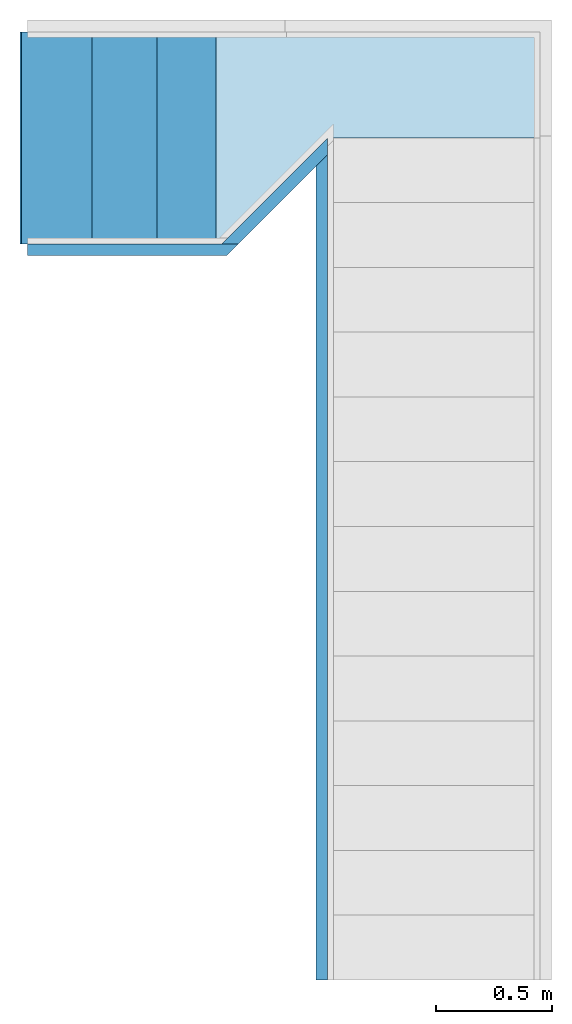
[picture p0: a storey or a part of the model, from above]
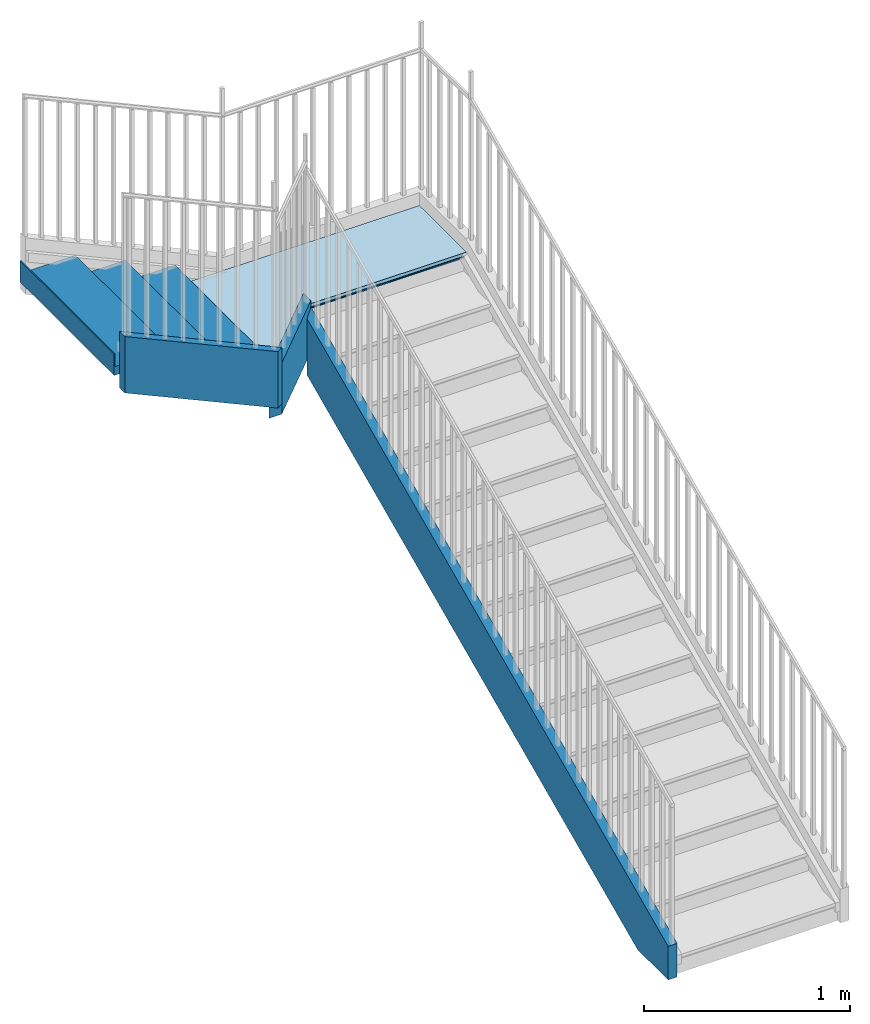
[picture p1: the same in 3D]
Properties of the parts of a building model (IFC2X3)

# File
Description: ViewDefinition [CoordinationView_V2.0]
File name: Project Number
Time: 2021-07-12T14:45:06
Written by: The EXPRESS Data Manager Version 5.02.0100.07 : 28 Aug 2013
Made in: 20180216_1515(x64) - Exporter 19.0.0.405 - 备用 UI 19.0.0.405
Comment: STEP Physical File produced by: The EXPRESS Data Manager Version 5.02.0100.07 : 28 Aug 2013 * Module: EDMstepFileFactory/EDMstandAlone * Creation date: Mon Jul 12 14:45:06 2021 * Host: DESKTOP-OMQ10H7 * Database: C:\Users\12580\AppData\Local\Temp\{0BB1D5D9-1BC5-407F-83F6-5A93C41D403B}\ifc * Database version: 5507 * Database creation date: Mon Jul 12 14:44:55 2021 * Schema: IFC2X3 * Model: DataRepository.ifc * Model creation date: Mon Jul 12 14:44:55 2021 * Header model: DataRepository.ifc_HeaderModel * Header model creation date: Mon Jul 12 14:44:55 2021 * EDMuser: sdai-user * EDMgroup: sdai-group * License ID and type: 5605 : Permanent license. Expiry date: * EDMstepFileFactory options: 020000

# IfcProject, Project Number
LongName: Project Name; Phase: Project Status

# IfcSite, 表面:237656
RefLatitude: 42, 21, 30, 344238; RefLongitude: -71, -3, -35, -194702; RefElevation: 0 ft

# IfcBuilding
Pset_BuildingCommon - NumberOfStoreys: 4

# IfcBuildingStorey (4)
Name | LongName | Elevation (ft)
HULL | HULL | -10
Level 1 | Level 1 | 0
Level 2 | Level 2 | 10
Sun Deck | Sun Deck | 20

# IfcBuildingElementProxy: 27" x 25" x 35", Dryer:27" x 25" x 35":377129
In: Level 2
Type - Classification: E1090400 Residential Equipment (Uniformat); Material: Metal - Paint Finish - Ivory, Glossy
Pset_BuildingElementProxyCommon - Reference: 27" x 25" x 35"

# IfcBuildingElementProxy: 27" x 25" x 35", Washer:27" x 25" x 35":376304
In: Level 2
Type - Classification: E1090400 Residential Equipment (Uniformat); Material: Metal - Paint Finish - Ivory, Matte
Pset_BuildingElementProxyCommon - Reference: 27" x 25" x 35"

# IfcBuildingElementProxy: 36" x 70", Refrigerator_built-in_SideBySide_stainlessrfa_5540:36" x 70":266599
In: Level 1
Type - Material: Metal - Stainless Steel, High Gloss Black
Pset_BuildingElementProxyCommon - Reference: 36" x 70"

# IfcBuildingElementProxy: 42_inch_plasma_tv_11107 (5)
Type - Material: glossy plastic, tv screen
Pset_BuildingElementProxyCommon - Reference: 42_inch_plasma_tv_11107
Name (42_inch_plasma_tv_11107:42_inch_plasma_tv_11107:...) | In
372576 | Sun Deck
372613 | Sun Deck
374357 | Level 2
375434 | Level 2
378181 | Level 2

# IfcBuildingElementProxy: 70039039_LED_TV_SONY_11909, 70039039_LED_TV_SONY_11909:70039039_LED_TV_SONY_11909:320596
In: Level 2
Material: Smooth - Black
Pset_BuildingElementProxyCommon - Reference: 70039039_LED_TV_SONY_11909

# IfcBuildingElementProxy: 72" (3)
In: Sun Deck
Material: Wood - Teak, Metal - Paint Finish - Dark Gray, Matte
Pset_BuildingElementProxyCommon - Reference: 72"
Name (Park Bench:72":...)
236447
236590
236649

# IfcBuildingElementProxy: Curvtec_Modular_Ceiling_with_lighting_11464, Curvtec_Modular_Ceiling_with_lighting_11464:Curvtec_Modular_Ceiling_with_lighting_11464:271074
In: Level 1
Type - Material: Glass - White, High Luminance, Wood Ceiling Black, Ceiling recess, Wood Ceiling
Pset_BuildingElementProxyCommon - Reference: Curvtec_Modular_Ceiling_with_lighting_11464

# IfcBuildingElementProxy: Mid_Size_Kitchen_-_Revit_2011_11227, Mid_Size_Kitchen_-_Revit_2011_11227:Mid_Size_Kitchen_-_Revit_2011_11227:266598
In: Level 1
Type - Material: Metal - Steel, Polished, range canopy, Stainless Steel Satin, Paint Black Glossy, Black Plastic (1), Brushed Aluminum Plastic, Cabinets - Handles, Wood - Cherry, Vidro Espelhado, Render Material 255-255-255, Stainless Steel, Cabinets, Dark Wood
Pset_BuildingElementProxyCommon - Reference: Mid_Size_Kitchen_-_Revit_2011_11227

# IfcBuildingElementProxy: Projection_Screen_4752, Projection_Screen_4752:Projection_Screen_4752:284235
In: Level 1
Type - Material: Screen, Case
Pset_BuildingElementProxyCommon - Reference: Projection_Screen_4752

# IfcBuildingElementProxy: RPC Notebook Computer (2)
In: Sun Deck
Pset_BuildingElementProxyCommon - Reference: RPC Notebook Computer
Name (RPC Notebook Computer:RPC Notebook Computer:...)
208535
208852

# IfcBuildingElementProxy: Scarlet Oak - 42' (13)
In: Level 1
Type - Classification: G2050500 Planting (Uniformat)
Pset_BuildingElementProxyCommon - Reference: Scarlet Oak - 42'
Name (RPC Tree - Deciduous:Scarlet Oak - 42':...)
322992
323077
323106
323141
323178
323237
323296
323366
323413
323432
323502
323537
323560

# IfcBuildingElementProxy: Standard, Cage Ladder:Standard:312129
In: Sun Deck
Pset_BuildingElementProxyCommon - Reference: Standard

# IfcBuildingElementProxy: Tall_Speaker_2545 (8)
In: Level 1
Type - Material: Speaker, Gloss White
Pset_BuildingElementProxyCommon - Reference: Tall_Speaker_2545
Name (Tall_Speaker_2545:Tall_Speaker_2545:...)
287609
287684
287761
287830
288329
288446
288509
288600

# IfcCovering: 复合天花板:GWB on Mtl. Stud (7)
PredefinedType: CEILING; Classification: C3030220 Suspended Ceilings - Gypsum Board (Uniformat); Material: Metal - Stud Layer 0.302083 ft, Gypsum Wall Board 0.0520833 ft
Pset_CoveringCommon - Reference: GWB on Mtl. Stud; Finish: Gypsum Wall Board;; TotalThickness: 0.354167 ft
Name (复合天花板:GWB on Mtl. Stud:...) | In
188560 | Level 2
189789 | Sun Deck
192301 | Sun Deck
267230 | Level 1
267281 | Level 1
301652 | Level 1
349367 | Level 2

# IfcDoor: 30" x 80", Single-Flush:30" x 80":341240
In: Level 2
Type - OperationType: SINGLE_SWING_LEFT; ParameterTakesPrecedence: no; Sizeable: no; Classification: C1020 Interior Doors (Uniformat); Material: Door - Frame, Door - Panel
Type - Single-Flush:30" x 80":341240 - PanelOperation: SWINGING
OverallHeight: 6.66667 ft; OverallWidth: 2.5 ft
Pset_DoorCommon - IsExternal: no; Reference: 30" x 80"

# IfcDoor: 30" x 80", Single-Glass 2:30" x 80":267189
In: Level 1
Type - OperationType: SINGLE_SWING_LEFT; ParameterTakesPrecedence: no; Sizeable: no; Classification: C1020 Interior Doors (Uniformat); Material: Door - Frame, Door - Panel, Glass
Type - Single-Glass 2:30" x 80":267189 - PanelOperation: SWINGING
OverallHeight: 6.66667 ft; OverallWidth: 2.5 ft
Pset_DoorCommon - IsExternal: no; Reference: 30" x 80"

# IfcDoor: 30" x 80" (2)
In: Level 2
Type - OperationType: SINGLE_SWING_RIGHT; ParameterTakesPrecedence: no; Sizeable: no; Classification: C1020 Interior Doors (Uniformat); Material: Door - Frame, Door - Panel
Type - Single-Flush:30" x 80":331799 - PanelOperation: SWINGING
OverallHeight: 6.66667 ft; OverallWidth: 2.5 ft
Pset_DoorCommon - IsExternal: no; Reference: 30" x 80"
Name (Single-Flush:30" x 80":...)
331799
341395

# IfcDoor: 30" x 80", Single-Flush:30" x 80":344412
In: Level 2
Type - OperationType: SINGLE_SWING_RIGHT; ParameterTakesPrecedence: no; Sizeable: no; Classification: C1020 Interior Doors (Uniformat); Material: Door - Frame, Door - Panel
Type - Single-Flush:30" x 80":344412 - PanelOperation: SWINGING
OverallHeight: 6.66667 ft; OverallWidth: 2.5 ft
Pset_DoorCommon - IsExternal: no; Reference: 30" x 80"

# IfcDoor: 30" x 84", Single-Glass 2:30" x 84":328122
In: Level 2
Type - OperationType: SINGLE_SWING_LEFT; ParameterTakesPrecedence: no; Sizeable: no; Classification: C1020 Interior Doors (Uniformat); Material: Door - Frame, Door - Panel, Glass
Type - Single-Glass 2:30" x 84":328122 - PanelOperation: SWINGING
OverallHeight: 7 ft; OverallWidth: 3 ft
Pset_DoorCommon - IsExternal: no; Reference: 30" x 84"

# IfcDoor: 30" x 84", Single-Glass 2:30" x 84":336054
In: Level 2
Type - OperationType: SINGLE_SWING_RIGHT; ParameterTakesPrecedence: no; Sizeable: no; Classification: C1020 Interior Doors (Uniformat); Material: Door - Frame, Door - Panel, Glass
Type - Single-Glass 2:30" x 84":336054 - PanelOperation: SWINGING
OverallHeight: 7 ft; OverallWidth: 3 ft
Pset_DoorCommon - IsExternal: no; Reference: 30" x 84"

# IfcDoor: 32" x 84" (2)
In: Level 1
Type - OperationType: SINGLE_SWING_RIGHT; ParameterTakesPrecedence: no; Sizeable: no; Classification: C1020 Interior Doors (Uniformat); Material: Door - Frame, Door - Panel
Type - Single-Flush:32" x 84":314709 - PanelOperation: SWINGING
OverallHeight: 7 ft; OverallWidth: 2.66667 ft
Pset_DoorCommon - IsExternal: no; Reference: 32" x 84"
Name (Single-Flush:32" x 84":...)
314709
314761

# IfcDoor: 48" x 84" (2)
In: Level 2
Type - ParameterTakesPrecedence: no; Sizeable: no; Classification: C1020 Interior Doors (Uniformat); Material: Door - Panel, Door - Frame
OverallHeight: 5 ft; OverallWidth: 4 ft
Pset_DoorCommon - IsExternal: no; Reference: 48" x 84"
Name (Bifold-4 Panel:48" x 84":...)
337613
339624

# IfcDoor: 60" x 84" (3)
In: Level 2
Type - ParameterTakesPrecedence: no; Sizeable: no; Classification: C1020 Interior Doors (Uniformat); Material: Door - Panel, Door - Frame
OverallHeight: 7 ft; OverallWidth: 5 ft
Pset_DoorCommon - IsExternal: no; Reference: 60" x 84"
Name (Bifold-4 Panel:60" x 84":...)
336918
371404
371428

# IfcDoor: 68" x 84" (4)
Type - ParameterTakesPrecedence: no; Sizeable: no; Classification: C1020 Interior Doors (Uniformat); Material: Glass, Door - Panel, Door - Frame
OverallHeight: 7 ft; OverallWidth: 5.66667 ft
Pset_DoorCommon - IsExternal: no; Reference: 68" x 84"
Name (Sliding-2 panel:68" x 84":...) | In
323940 | Level 2
323982 | Level 2
325066 | Level 1
325091 | Level 1

# IfcDoor: 72" x 84" (10)
Type - ParameterTakesPrecedence: no; Sizeable: no; Classification: C1020 Interior Doors (Uniformat); Material: Glass, Door - Panel, Door - Frame
OverallHeight: 7 ft; OverallWidth: 10 ft
Pset_DoorCommon - IsExternal: yes; Reference: 72" x 84"
Name (Sliding-2 panel:72" x 84":...) | In
312039 | Level 1
312078 | Level 1
312933 | Level 1
313002 | Level 1
322042 | Level 2
322064 | Level 2
322137 | Level 2
322168 | Level 2
322806 | Sun Deck
322843 | Sun Deck

# IfcFlowTerminal: 100W - 120V (24)
In: Level 1
Type - Classification: D5020220 Lighting - Incandescent (Uniformat); Material: Metal - Paint Finish - Dark Gray, Matte, Glass - White, High Luminance
Pset_DistributionFlowElementCommon - Reference: 100W - 120V
Name (Ceiling Light - Flat Round:100W - 120V:...)
272236
272435
272723
272951
273287
273575
274187
275483
275795
276107
276755
276983
277403
277763
278135
278411
302545
302617
302785
303025
303313
303577
303865
304669

# IfcFlowTerminal: 100W - 277V (41)
In: Level 2
Type - Classification: D5020220 Lighting - Incandescent (Uniformat); Material: Metal - Paint Finish - Dark Gray, Matte, Glass - White, High Luminance
Pset_DistributionFlowElementCommon - Reference: 100W - 277V
Name (Ceiling Light - Flat Round:100W - 277V:...)
350810
350911
351163
351763
351955
352207
352423
352699
352927
353167
353551
353815
353959
354559
355183
355351
356023
356671
356839
356995
358003
358255
358591
358831
359455
359683
359911
360151
360655
360955
361351
361843
362431
362827
363091
363391
363547
363703
364075
364987
365203

# IfcFlowTerminal: 15" Seat Height (4)
Classification: D2010110 Water Closets - Single (Uniformat); Material: Porcelain - Ivory, Laminate - Ivory, Matte, Metal - Steel, Polished
Pset_DistributionFlowElementCommon - Reference: 15" Seat Height
Name (Toilet-Commercial-Wall-3D:15" Seat Height:...) | In
315608 | Level 1
331035 | Level 2
331502 | Level 2
341191 | Level 2

# IfcFlowTerminal: 30" x 60" (2)
In: Level 2
Classification: D2010110 Water Closets - Single (Uniformat); Material: Porcelain - Ivory
Pset_DistributionFlowElementCommon - Reference: 30" x 60"
Name (Tub-Free Standing-3D:30" x 60":...)
329077
332994

# IfcFlowTerminal: 52quot_Surface_Ceiling_Fan_Retro_look_11276 (13)
Type - Material: Light Bulb, Glass - Frosted, Black Out, Plastic - White
Pset_DistributionFlowElementCommon - Reference: 52quot_Surface_Ceiling_Fan_Retro_look_11276
Name (52quot_Surface_Ceiling_Fan_Retro_look_11276:52quot_Surface_Ceiling_Fan_Retro_look_11276:...) | In
299501 | Level 1
299546 | Level 1
300126 | Level 1
300866 | Level 1
302015 | Level 1
302113 | Level 1
366261 | Level 2
366329 | Level 2
366649 | Level 2
367009 | Level 2
367279 | Level 2
367749 | Level 2
368369 | Level 2

# IfcFlowTerminal: 60W - 120V (12)
In: Sun Deck
Type - Classification: D5020220 Lighting - Incandescent (Uniformat); Material: Metal - Paint Finish - Dark Gray, Matte, Glass - White, High Luminance
Pset_DistributionFlowElementCommon - Reference: 60W - 120V
Name (Ceiling Light - Flat Round:60W - 120V:...)
211935
212036
212252
212480
212948
213164
213344
213536
214304
214616
215036
215408

# IfcFurnishingElement: 24" Depth (5)
Type - ElementType: 24" Depth; Classification: C1030400 Fabricated Cabinets & Counters (Uniformat); Material: Counter Top
Name (Vanity Counter Top w Round Sink Hole:24" Depth:...) | In
317033 | Level 1
329369 | Level 2
332200 | Level 2
332346 | Level 2
377366 | Level 2

# IfcFurnishingElement: 24" x 24", Table-End:24" x 24":348298
In: Level 2
Type - ElementType: 24" x 24"; Classification: E2020200 Furniture & Accessories (Uniformat); Material: Laminate - Ivory, Matte, Wood - Birch

# IfcFurnishingElement: 27", Television:27":369105
In: Level 2
Type - ElementType: 27"; Classification: E2020200 Furniture & Accessories (Uniformat); Material: Plastic - Gray, Glass

# IfcFurnishingElement: 30" x 84" x 22", Table-Dining:30" x 84" x 22":279648
In: Level 1
Type - ElementType: 30" x 84" x 22"; Classification: E2020200 Furniture & Accessories (Uniformat); Material: Metal - Chrome, Glass - Clear, Grey

# IfcFurnishingElement: 36" Diameter (2)
In: Level 2
Type - ElementType: 36" Diameter; Classification: E2020200 Furniture & Accessories (Uniformat); Material: Metal - Chrome, Wood - Birch
Name (Table-Round:36" Diameter:...)
375108
375185

# IfcFurnishingElement: 36" Diameter (3)
Type - ElementType: 36" Diameter; Classification: E2020200 Furniture & Accessories (Uniformat); Material: Wood - Pine, Laminate - Linen, Matte
Name (Table-Dining Round w Chairs:36" Diameter:...) | In
233616 | Level 1
233758 | Sun Deck
233853 | Sun Deck

# IfcFurnishingElement: 48" (2)
Type - ElementType: 48"; Classification: C1030410 Cabinets (Uniformat); Material: Cabinets - Handles, Cabinets
Name (Vanity Cabinet-Double Door & 4 Drawer:48":...) | In
316380 | Level 1
341020 | Level 2

# IfcFurnishingElement: 48" (3)
In: Level 2
Type - ElementType: 48"; Classification: C1030410 Cabinets (Uniformat); Material: Cabinets, Cabinets - Handles
Name (Base Cabinet-Double Door Sink Unit:48":...)
329719
332070
377529

# IfcFurnishingElement: 72", Sofa:72":378009
In: Level 2
Type - ElementType: 72"; Classification: E2020200 Furniture & Accessories (Uniformat); Material: Wood - Cherry, Textile - Linen, Smooth

# IfcFurnishingElement: 72" x 72" x 24" (2)
In: Level 2
Type - ElementType: 72" x 72" x 24"; Classification: E2020200 Furniture & Accessories (Uniformat); Material: Metal - Chrome, Glass - Clear, Grey
Name (Entertainment Center:72" x 72" x 24":...)
334129
345260

# IfcFurnishingElement: 82" x 36" (2)
In: Level 2
Type - ElementType: 82" x 36"; Classification: E2020200 Furniture & Accessories (Uniformat); Material: Wood - Birch, Textile - White
Name (Bed-Bunk:82" x 36":...)
343888
344183

# IfcFurnishingElement: BED_9020 (2)
In: Level 2
Type - ElementType: BED_9020; Material: Metal - Paint Finish - Ivory, Glossy, Glass - White, High Luminance, ss, black, shine, garment, wood brown
Name (BED_9020:BED_9020:...)
319784
326286

# IfcFurnishingElement: Chair-Breuer (26)
Type - ElementType: Chair-Breuer; Classification: E2020200 Furniture & Accessories (Uniformat); Material: Textile - Bamboo Weave, Metal - Chrome
Name (Chair-Breuer:Chair-Breuer:...) | In
233618 | Level 1
233619 | Level 1
233620 | Level 1
233621 | Level 1
233622 | Level 1
233623 | Level 1
233760 | Sun Deck
233761 | Sun Deck
233762 | Sun Deck
233763 | Sun Deck
233764 | Sun Deck
233765 | Sun Deck
233855 | Sun Deck
233856 | Sun Deck
233857 | Sun Deck
233858 | Sun Deck
233859 | Sun Deck
233860 | Sun Deck
280343 | Level 1
280508 | Level 1
280549 | Level 1
280588 | Level 1
280641 | Level 1
280700 | Level 1
280793 | Level 1
280983 | Level 1

# IfcFurnishingElement: Chair-Corbu (6)
In: Level 2
Type - ElementType: Chair-Corbu; Classification: E2020200 Furniture & Accessories (Uniformat); Material: Textile - Black, Metal - Chrome
Name (Chair-Corbu:Chair-Corbu:...)
334675
339712
341920
342243
374127
374248

# IfcFurnishingElement: Chair-Executive, Chair-Executive:Chair-Executive:346257
In: Level 2
Type - ElementType: Chair-Executive; Classification: E2020200 Furniture & Accessories (Uniformat); Material: Plastic - Black, Textile - Slate Blue

# IfcFurnishingElement: Coffee_table_10605, Coffee_table_10605:Coffee_table_10605:305432
In: Level 1
Type - ElementType: Coffee_table_10605; Material: Speaker Body

# IfcFurnishingElement: Histoire_Round_Bed_10479, Histoire_Round_Bed_10479:Histoire_Round_Bed_10479:325919
In: Level 2
Type - ElementType: Histoire_Round_Bed_10479; Material: Blue Leather, Dark Wood

# IfcFurnishingElement: Hot_Tub_4137, Hot_Tub_4137:Hot_Tub_4137:264282
In: Level 1
Type - ElementType: Hot_Tub_4137; Material: Site - Water, Wood - Pine

# IfcFurnishingElement: Modern_Office_Desk_8428, Modern_Office_Desk_8428:Modern_Office_Desk_8428:370810
In: Level 2
Type - ElementType: Modern_Office_Desk_8428; Material: Glass, Metal, Cherry

# IfcFurnishingElement: Sofa_6855, Sofa_6855:Sofa_6855:264052
In: Level 1
Type - ElementType: Sofa_6855; Material: Blue Leather

# IfcFurnishingElement: Theater_Seating_2459, Theater_Seating_2459:Theater_Seating_2459:286273
In: Level 1
Type - ElementType: Theater_Seating_2459; Material: Default

# IfcFurnishingElement: armchair_12444 (3)
In: Sun Deck
Type - ElementType: armchair_12444; Material: legs, cushion 9, cushion 6
Name (armchair_12444:armchair_12444:...)
373716
373787
373836

# IfcFurnishingElement: pool_table_11855, pool_table_11855:pool_table_11855:278966
In: Level 1
Type - ElementType: pool_table_11855; Material: wood 26t, felt, pocket

# IfcMember: 楼梯:7" max riser 11" tread:54873 (28)
Classification: C Interiors (Uniformat); Material: Metal - Aluminum
Pset_MemberCommon - Reference: 7" max riser 11" tread; LoadBearing: yes; IsExternal: yes
Name (楼梯:7" max riser 11" tread:...) | In
162685:1 | Level 1 | Pset_MemberCommon - Span: 0.166667 ft; Slope: 0 deg
162685:2 | Level 1 | Pset_MemberCommon - Span: 0.166667 ft; Slope: 0 deg
163019:1 | Level 1 | Pset_MemberCommon - Span: 0.166667 ft; Slope: 0 deg
163019:2 | Level 1 | Pset_MemberCommon - Span: 0.166667 ft; Slope: 0 deg
163560:1 | Level 1 | Pset_MemberCommon - Span: 0.166667 ft; Slope: 0 deg
163560:2 | Level 1 | Pset_MemberCommon - Span: 0.166667 ft; Slope: 0 deg
168170:1 | HULL
168170:2 | HULL
168170:3 | HULL
168170:4 | HULL | Pset_MemberCommon - Span: 1 ft; Slope: 0 deg
168392:1 | Level 1
168392:2 | Level 1
168392:3 | Level 1 | Pset_MemberCommon - Span: 1 ft; Slope: 0 deg
168392:4 | Level 1
182033:1 | Level 2
182033:2 | Level 2
182033:3 | Level 2 | Pset_MemberCommon - Span: 1 ft; Slope: 0 deg
182033:4 | Level 2
199630:1 | Level 1
199630:2 | Level 1
199630:3 | Level 1
199630:4 | Level 1 | Pset_MemberCommon - Span: 1 ft; Slope: 0 deg
202250:1 | Level 2
202250:2 | Level 2
202250:3 | Level 2 | Pset_MemberCommon - Span: 1 ft; Slope: 0 deg
202250:4 | Level 2 | Pset_MemberCommon - Span: 0.166667 ft; Slope: 0 deg
314511:1 | Level 1 | Pset_MemberCommon - Span: 0.166667 ft; Slope: 0 deg
314511:2 | Level 1 | Pset_MemberCommon - Span: 0.166667 ft; Slope: 0 deg

# IfcOpeningElement: Opening (79)
Name | In
2 x  | Level 1 | Classification: B1010 Floor Construction (Uniformat)
5 x  | Level 2 | Classification: B1010 Floor Construction (Uniformat)
楼板:LW Concrete on Metal Deck:175324:2 | Level 2 | Classification: B1010 Floor Construction (Uniformat)
Bifold-4 Panel:60" x 84":371404:1 | Level 2
Bifold-4 Panel:60" x 84":371428:1 | Level 2
基本墙:Generic - 4" Brick:307458 | Level 2 | Classification: B2010 Exterior Walls (Uniformat)
基本墙:Generic - 4" Brick:309413 | Level 1 | Classification: B2010 Exterior Walls (Uniformat)
Vanity Counter Top w Round Sink Hole:24" Depth:317033:1 | Level 1 | Classification: C1030400 Fabricated Cabinets & Counters (Uniformat)
楼板:LW Concrete on Metal Deck:317237:2 | Level 2 | Classification: B1010 Floor Construction (Uniformat)
 | Sun Deck | Classification: B1010 Floor Construction (Uniformat)
Single-Flush:30" x 80":344412:1 | Level 2
Vanity Counter Top w Round Sink Hole:24" Depth:329369:1 | Level 2 | Classification: C1030400 Fabricated Cabinets & Counters (Uniformat)
Vanity Counter Top w Round Sink Hole:24" Depth:332200:1 | Level 2 | Classification: C1030400 Fabricated Cabinets & Counters (Uniformat)
Vanity Counter Top w Round Sink Hole:24" Depth:332346:1 | Level 2 | Classification: C1030400 Fabricated Cabinets & Counters (Uniformat)
Single-Flush:30" x 80":341240:1 | Level 2
Vanity Counter Top w Round Sink Hole:24" Depth:377366:1 | Level 2 | Classification: C1030400 Fabricated Cabinets & Counters (Uniformat)
Bifold-4 Panel:48" x 84":339624:1 | Level 2
Single-Glass 2:30" x 80":267189:1 | Level 1
Slider with Trim:48" x 48":331066:1 | Level 2
Sliding-2 panel:72" x 84":322042:1 | Level 2
Slider with Trim:48" x 48":322226:1 | Level 2
Slider with Trim:48" x 48":322263:1 | Level 2
Slider with Trim:48" x 48":322329:1 | Level 2
Slider with Trim:48" x 48":322571:1 | Level 2
Slider with Trim:48" x 48":337709:1 | Level 2
Slider with Trim:48" x 48":342144:1 | Level 2
Sliding-2 panel:72" x 84":322137:1 | Level 2
Sliding-2 panel:72" x 84":322168:1 | Level 2
Sliding-2 panel:72" x 84":322064:1 | Level 2
Slider with Trim:48" x 48":322369:1 | Level 2
Slider with Trim:48" x 48":322411:1 | Level 2
Slider with Trim:48" x 48":322455:1 | Level 2
Slider with Trim:48" x 48":331716:1 | Level 2
Slider with Trim:48" x 48":342172:1 | Level 2
Sliding-2 panel:68" x 84":323982:1 | Level 2
Sliding-2 panel:68" x 84":323940:1 | Level 2
Slider with Trim:48" x 48":323922:1 | Level 2
Slider with Trim:48" x 48":322567:1 | Level 2
Slider with Trim:48" x 48":342203:1 | Level 2
Slider with Trim:48" x 48":342191:1 | Level 2
Sliding-2 panel:72" x 84":313002:1 | Level 1
Slider with Trim:48" x 48":314223:1 | Level 1
Slider with Trim:48" x 48":314252:1 | Level 1
Sliding-2 panel:72" x 84":312039:1 | Level 1
Sliding-2 panel:72" x 84":312078:1 | Level 1
Sliding-2 panel:72" x 84":312933:1 | Level 1
Slider with Trim:48" x 48":314029:1 | Level 1
Slider with Trim:48" x 48":314059:1 | Level 1
Slider with Trim:48" x 48":314088:1 | Level 1
Slider with Trim:48" x 48":314110:1 | Level 1
Slider with Trim:36" x 48":312009:1 | Level 1
Slider with Trim:36" x 48":312024:1 | Level 1
Sliding-2 panel:68" x 84":325066:1 | Level 1
Sliding-2 panel:68" x 84":325091:1 | Level 1
Slider with Trim:48" x 48":314162:1 | Level 1
Slider with Trim:48" x 48":325255:1 | Level 1
Slider with Trim:48" x 48":325135:1 | Level 1
Slider with Trim:48" x 48":325177:1 | Level 1
Slider with Trim:60" x 48":322711:1 | Sun Deck
Slider with Trim:60" x 48":322750:1 | Sun Deck
Sliding-2 panel:72" x 84":322806:1 | Sun Deck
Sliding-2 panel:72" x 84":322843:1 | Sun Deck
Slider with Trim:48" x 48":322792:1 | Sun Deck
Slider with Trim:48" x 48":322796:1 | Sun Deck
Slider with Trim:48" x 48":314132:1 | Level 1
Slider with Trim:48" x 48":325219:1 | Level 1
Single-Flush:32" x 84":314761:1 | Level 1
Single-Flush:32" x 84":314709:1 | Level 1
Single-Glass 2:30" x 84":328122:1 | Level 2
Single-Glass 2:30" x 84":336054:1 | Level 2
Single-Flush:30" x 80":341395:1 | Level 2
Single-Flush:30" x 80":331799:1 | Level 2
Bifold-4 Panel:60" x 84":336918:1 | Level 2
Bifold-4 Panel:48" x 84":337613:1 | Level 2

# IfcRailing: 栏杆扶手:Handrail - Rectangular (23)
Classification: C2010400 Stair Handrails/Balustrades (Uniformat)
Pset_RailingCommon - IsExternal: no; Reference: Handrail - Rectangular; Height: 4 ft
Name (栏杆扶手:Handrail - Rectangular:...) | In
162701 | Level 1
162705 | Level 1
163027 | Level 1
163031 | Level 1
168229 | HULL
168233 | HULL
168422 | Level 1
168426 | Level 1
170974 | Level 1
171574 | Level 1
172054 | Level 1
179988 | Level 2
182085 | Level 2
182089 | Level 2
200027 | Level 1
200031 | Level 1
201111 | Level 2
202295 | Level 2
202299 | Level 2
202742 | Sun Deck
203479 | Sun Deck
314527 | Level 1
314531 | Level 1

# IfcSlab: 楼板:3" LW Concrete on 2" Metal Deck, 楼板:3" LW Concrete on 2" Metal Deck:324292
In: Sun Deck
PredefinedType: FLOOR; Classification: B1010 Floor Construction (Uniformat); Material: Carpet (2) 0.25 ft
Pset_SlabCommon - LoadBearing: no; IsExternal: no; Reference: 3" LW Concrete on 2" Metal Deck

# IfcSlab: 楼板:LW Concrete on Metal Deck (10)
PredefinedType: FLOOR; Classification: B1010 Floor Construction (Uniformat); Material: Metal - Deck 0.333333 ft, Carpet (2) 0.0104167 ft
Pset_SlabCommon - LoadBearing: no; IsExternal: no; Reference: LW Concrete on Metal Deck
Name (楼板:LW Concrete on Metal Deck:...) | In | PitchAngle (deg)
161527 | Level 1 | 0
162236 | Level 1
169581 | Level 1 | 0
175324 | Level 2
176802 | Level 2 | 0
178148 | Level 1 | 0
179185 | Level 2
202447 | Sun Deck | 0
317237 | Level 2
318822 | Level 2 | 0

# IfcSlab: 楼梯:7" max riser 11" tread:54873 (5)
PredefinedType: LANDING; Classification: C Interiors (Uniformat); Material: Metal - Aluminum
Pset_SlabCommon - Reference: 7" max riser 11" tread; IsExternal: yes
Name (楼梯:7" max riser 11" tread:...) | In
168170:1 | HULL
168392:1 | Level 1
182033:1 | Level 2
199630:1 | Level 1
202250:1 | Level 2

# IfcStair: 楼梯:7" max riser 11" tread:54873 (9)
Classification: C Interiors (Uniformat)
Pset_StairCommon - Reference: 7" max riser 11" tread; IsExternal: yes; TreadLength: 0.916667 ft
Name (楼梯:7" max riser 11" tread:...) | In | NumberOfRiser | NumberOfTreads | RiserHeight (ft)
162685 | Level 1 | 3 | 2 | 0.558824
163019 | Level 1 | 3 | 2 | 0.558824
163560 | Level 1 | 3 | 2 | 0.558824
168170 | HULL | 18 | 17 | 0.416667
168392 | Level 1 | 18 | 17 | 0.555556
182033 | Level 2 | 18 | 17 | 0.555556
199630 | Level 1 | 18 | 17 | 0.569444
202250 | Level 2 | 18 | 17 | 0.555556
314511 | Level 1 | 3 | 2 | 0.555556

# IfcStairFlight: 楼梯:7" max riser 11" tread:54873 (14)
Classification: C Interiors (Uniformat); Material: Metal - Aluminum
Pset_StairFlightCommon - Reference: 7" max riser 11" tread; TreadLength: 0.916667 ft; TreadLengthAtOffset: 0.916667 ft; TreadLengthAtInnerSide: 0.0833333 ft; NosingLength: 0.916667 ft
Name (楼梯:7" max riser 11" tread:...) | In | NumberOfRiser | NumberOfTreads | RiserHeight (ft) = Pset_StairFlightCommon, RiserHeight (ft) | TreadLength (ft) | Pset_StairFlightCommon, NumberOfRiser | Pset_StairFlightCommon, NumberOfTreads | WalkingLineOffset (ft) | WaistThickness (ft)
162685:1 | Level 1 | 3 | 2 | 0.558824 | 0.916667 | 3 | 2 | 1.79167 | 3.58333
163019:1 | Level 1 | 3 | 2 | 0.558824 | 0.916667 | 3 | 2 | 1.75 | 3.5
163560:1 | Level 1 | 3 | 2 | 0.558824 | 0.916667 | 3 | 2 | 2 | 4
168170:1 | HULL | 14 | 13 | 0.416667 | 0.916667 | 18 | 17 | 1.5 | 3
168170:2 | HULL | 4 | 3 | 0.416667 | 0.916667 | 18 | 17 | 1.5 | 3
168392:1 | Level 1 | 4 | 3 | 0.555556 | 0.916667 | 18 | 17 | 1.5 | 3
168392:2 | Level 1 | 14 | 13 | 0.555556 | 0.916667 | 18 | 17 | 1.5 | 3
182033:1 | Level 2 | 4 | 3 | 0.555556 | 0.951389 | 18 | 17 | 1.5 | 3
182033:2 | Level 2 | 14 | 13 | 0.555556 | 0.916667 | 18 | 17 | 1.5 | 3
199630:1 | Level 1 | 16 | 15 | 0.569444 | 0.916667 | 18 | 17 | 1.5 | 3
199630:2 | Level 1 | 2 | 1 | 0.569444 | 0.916667 | 18 | 17 | 1.5 | 3
202250:1 | Level 2 | 2 | 1 | 0.555556 | 0.916667 | 18 | 17 | 1.5 | 3
202250:2 | Level 2 | 16 | 15 | 0.555556 | 0.916667 | 18 | 17 | 1.5 | 3
314511:1 | Level 1 | 3 | 2 | 0.555556 | 0.977867 | 3 | 2 | 1.75 | 3.5

# IfcWallStandardCase: 基本墙:Generic - 4" Brick (44)
Type - PredefinedType: STANDARD; Material: Paint 0.333333 ft, Paints and Coatings 0.166667 ft
Classification: B2010 Exterior Walls (Uniformat)
Pset_WallCommon - Reference: Generic - 4" Brick; LoadBearing: no; IsExternal: no
Name (基本墙:Generic - 4" Brick:...) | In | ExtendToStructure
161342 | Level 1 | no
161385 | Level 1 | no
161434 | Level 1 | no
161481 | Level 1 | no
163274 | Level 1 | yes
169023 | Level 1 | yes
169086 | Level 1 | yes
169295 | Level 1 | yes
169467 | Level 1 | yes
169516 | Level 1 | yes
169564 | Level 1 | yes
201977 | Level 2 | no
202191 | Level 2 | no
267019 | Level 1 | yes
307288 | Level 2 | no
307338 | Level 2 | no
307390 | Level 2 | no
307434 | Level 2 | no
307448 | Level 2 | no
307453 | Level 2 | no
307458 | Level 2 | no
307463 | Level 2 | no
307783 | Level 1 | yes
307841 | Level 1 | no
307897 | Level 1 | yes
307906 | Level 1 | no
307911 | Level 1 | no
309315 | Level 1 | yes
309359 | Level 1 | yes
309413 | Level 1 | no
309418 | Level 1 | yes
310853 | Sun Deck | no
310926 | Sun Deck | no
310995 | Sun Deck | no
311076 | Sun Deck | no
311140 | Sun Deck | no
311145 | Sun Deck | no
311150 | Sun Deck | no
311155 | Sun Deck | no
311675 | Level 1 | yes
314343 | Level 1 | yes
314392 | Level 1 | yes
314691 | Level 1 | yes
344382 | Level 2 | no

# IfcWallStandardCase: 基本墙:Interior - 3 1/8" Partition (1-hr) (23)
In: Level 2
Type - PredefinedType: STANDARD; Material: Gypsum Wall Board 0.0416667 ft, Gypsum Wall Board 0.0208333 ft, Metal - Stud Layer 0.135417 ft, Gypsum Wall Board 0.0208333 ft, Gypsum Wall Board 0.0416667 ft
Classification: C1010145 Partitions - Drywall w/ Metal Stud (Uniformat)
Pset_WallCommon - LoadBearing: no; ExtendToStructure: no; IsExternal: no; Reference: Interior - 3 1/8" Partition (1-hr)
Name (基本墙:Interior - 3 1/8" Partition (1-hr):...)
320325
327329
327517
327601
330925
331646
336532
336579
337480
337533
339567
339606
340040
341836
342554
342596
342631
342696
342759
342805
342927
371281
371325

# IfcWindow: 36" x 48" (2)
In: Level 1
Type - ParameterTakesPrecedence: no; Sizeable: no; Classification: B2020100 Windows (Uniformat); Material: Glass, Sash, Trim
OverallHeight: 4 ft; OverallWidth: 3 ft
Pset_WindowCommon - IsExternal: no; Reference: 36" x 48"
Name (Slider with Trim:36" x 48":...)
312009
312024

# IfcWindow: 48" x 48" (30)
Type - ParameterTakesPrecedence: no; Sizeable: no; Classification: B2020100 Windows (Uniformat); Material: Glass, Sash, Trim
OverallHeight: 4 ft; OverallWidth: 4 ft
Pset_WindowCommon - IsExternal: no; Reference: 48" x 48"
Name (Slider with Trim:48" x 48":...) | In
314029 | Level 1
314059 | Level 1
314088 | Level 1
314110 | Level 1
314132 | Level 1
314162 | Level 1
314223 | Level 1
314252 | Level 1
322226 | Level 2
322263 | Level 2
322329 | Level 2
322369 | Level 2
322411 | Level 2
322455 | Level 2
322567 | Level 2
322571 | Level 2
322792 | Sun Deck
322796 | Sun Deck
323922 | Level 2
325135 | Level 1
325177 | Level 1
325219 | Level 1
325255 | Level 1
331066 | Level 2
331716 | Level 2
337709 | Level 2
342144 | Level 2
342172 | Level 2
342191 | Level 2
342203 | Level 2

# IfcWindow: 60" x 48" (2)
In: Sun Deck
Type - ParameterTakesPrecedence: no; Sizeable: no; Classification: B2020100 Windows (Uniformat); Material: Glass, Sash, Trim
OverallHeight: 4 ft; OverallWidth: 5 ft
Pset_WindowCommon - IsExternal: no; Reference: 60" x 48"
Name (Slider with Trim:60" x 48":...)
322711
322750
